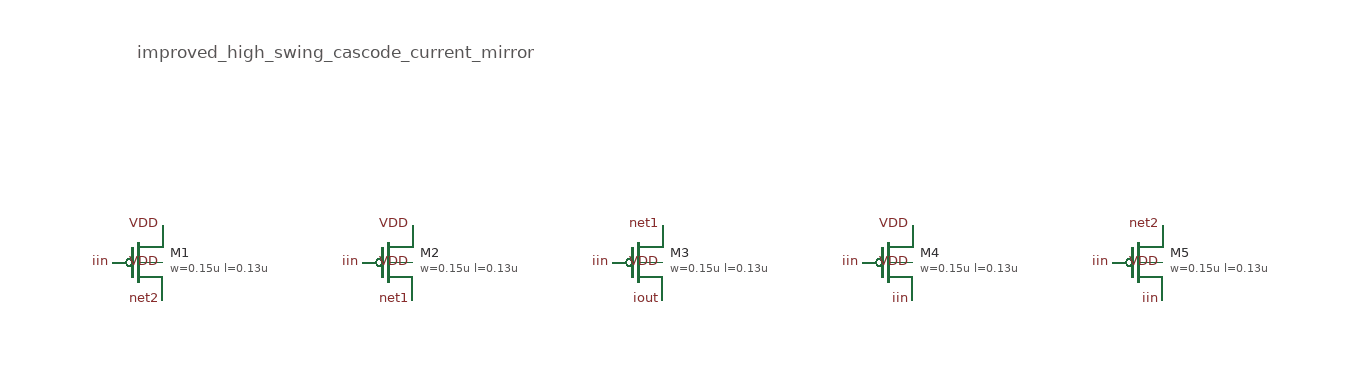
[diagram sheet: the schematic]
v {xschem version=3.4.6 file_version=1.2}
G {}
K {}
V {}
S {}
E {}
T {improved_high_swing_cascode_current_mirror} 0 -180 0 0 0.4 0.4 {}
C {devices/title.sym} 0 90 0 0 {name=l1 author="Copyright 2026 MacAnalog Research Group"}
C {sg13g2_pr/sg13_lv_pmos.sym} 0 0 0 0 {name=M1 model=sg13_lv_pmos spiceprefix=X w=0.15u l=0.13u ng=1 m=1}
C {sg13g2_pr/sg13_lv_pmos.sym} 200 0 0 0 {name=M2 model=sg13_lv_pmos spiceprefix=X w=0.15u l=0.13u ng=1 m=1}
C {sg13g2_pr/sg13_lv_pmos.sym} 400 0 0 0 {name=M3 model=sg13_lv_pmos spiceprefix=X w=0.15u l=0.13u ng=1 m=1}
C {sg13g2_pr/sg13_lv_pmos.sym} 600 0 0 0 {name=M4 model=sg13_lv_pmos spiceprefix=X w=0.15u l=0.13u ng=1 m=1}
C {sg13g2_pr/sg13_lv_pmos.sym} 800 0 0 0 {name=M5 model=sg13_lv_pmos spiceprefix=X w=0.15u l=0.13u ng=1 m=1}
C {devices/lab_wire.sym} -20 0 0 0 {name=lg1 lab=iin}
C {devices/lab_wire.sym} 20 30 0 0 {name=ld1 lab=net2}
C {devices/lab_wire.sym} 20 -30 0 0 {name=ls1 lab=VDD}
C {devices/lab_wire.sym} 20 0 0 0 {name=lb1 lab=VDD}
C {devices/lab_wire.sym} 180 0 0 0 {name=lg2 lab=iin}
C {devices/lab_wire.sym} 220 30 0 0 {name=ld2 lab=net1}
C {devices/lab_wire.sym} 220 -30 0 0 {name=ls2 lab=VDD}
C {devices/lab_wire.sym} 220 0 0 0 {name=lb2 lab=VDD}
C {devices/lab_wire.sym} 380 0 0 0 {name=lg3 lab=iin}
C {devices/lab_wire.sym} 420 30 0 0 {name=ld3 lab=iout}
C {devices/lab_wire.sym} 420 -30 0 0 {name=ls3 lab=net1}
C {devices/lab_wire.sym} 420 0 0 0 {name=lb3 lab=VDD}
C {devices/lab_wire.sym} 580 0 0 0 {name=lg4 lab=iin}
C {devices/lab_wire.sym} 620 30 0 0 {name=ld4 lab=iin}
C {devices/lab_wire.sym} 620 -30 0 0 {name=ls4 lab=VDD}
C {devices/lab_wire.sym} 620 0 0 0 {name=lb4 lab=VDD}
C {devices/lab_wire.sym} 780 0 0 0 {name=lg5 lab=iin}
C {devices/lab_wire.sym} 820 30 0 0 {name=ld5 lab=iin}
C {devices/lab_wire.sym} 820 -30 0 0 {name=ls5 lab=net2}
C {devices/lab_wire.sym} 820 0 0 0 {name=lb5 lab=VDD}
